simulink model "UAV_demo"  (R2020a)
settings: Solver=FixedStepAuto  StartTime=0.0  StopTime=30  FixedStep=1e-2  RelTol=1e-3
libraries: simulink x7, shared6dof x1

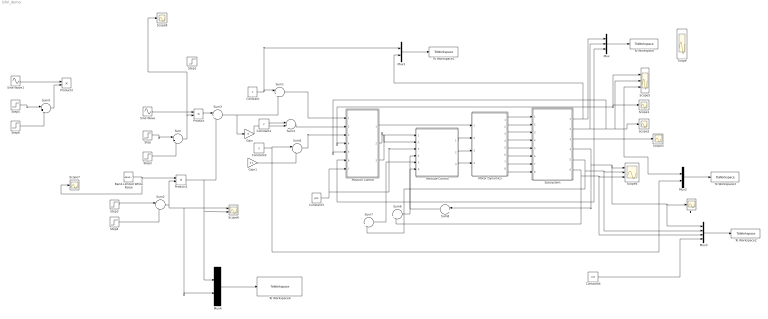
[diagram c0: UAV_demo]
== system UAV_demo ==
  Attitude Control : Subsystem
  Band-Limited White Noise : simulink/Sources/Band-Limited White Noise  Cov=[0.1]  Ts=0.1  seed=[23341]
  Constant : Constant
  Constant1 : Constant  Value=2
  Constant2 : Constant  Value=5
  Constant3 : Constant  Value=pi/4
  Constant4 : Constant  Value=0.8
  Gain : Gain
  Gain1 : Gain  Gain=0.1
  Motor Dynamics : Subsystem
  Mux : Mux  Inputs=3
  Mux1 : Mux  Inputs=2
  Mux2 : Mux  Inputs=2
  Mux3 : Mux
  Mux4 : Mux  Inputs=2
  Position Control : Subsystem
  Product : Product
  Product1 : Product
  Product2 : Product
  Scope : Scope  NumInputPorts=3
  Scope{1..3,7..8} (5 alike) : Scope
  Scope4 : Scope  NumInputPorts=3
  Scope5 : Scope  NumInputPorts=3
  Scope6 : Scope  NumInputPorts=2
  Sine Wave : Sin  Amplitude=0.5  Phase=pi/2  SampleTime=0
  Sine Wave1 : Sin  Amplitude=-0.01  SampleTime=0
  Step : Step  Time=8  After=2  SampleTime=0
  Step1 : Step  Time=0  After=10  SampleTime=0
  Step2 : Step  Time=9  After=-2  SampleTime=0
  Step3 : Step  Time=8  SampleTime=0
  Step4 : Step  Time=8.5  After=-1  SampleTime=0
  Step5 : Step  Time=8  After=2  SampleTime=0
  Step6 : Step  Time=8.5  After=-2  SampleTime=0
  Subsystem : Subsystem
  Sum{,1..9} (10 alike) : Sum  Inputs=|++
  To Workspace : ToWorkspace  VariableName=xyz  SampleTime=-1
  To Workspace1 : ToWorkspace  VariableName=x  SampleTime=-1
  To Workspace2 : ToWorkspace  VariableName=theta  SampleTime=-1
  To Workspace3 : ToWorkspace  VariableName=z  SampleTime=-1
  To Workspace4 : ToWorkspace  VariableName=gu  SampleTime=-1
  横滚角 : Scope
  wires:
  Position Control/2(Roll des) -> Attitude Control/1(Roll des)
  Position Control/3(Pitch des) -> Attitude Control/2(Pitch des)
  Attitude Control/1(Delta Omga roll) -> Motor Dynamics/2(Delta Omga roll)
  Position Control/1(OmegaF) -> Motor Dynamics/1(Delta OmgaF)
  Motor Dynamics/1(F1) -> Subsystem/1(Forces1)
  Motor Dynamics/2(F2) -> Subsystem/2(Forces2)
  Motor Dynamics/3(F3) -> Subsystem/3(Forces3)
  Motor Dynamics/4(F4) -> Subsystem/4(Forces4)
  Motor Dynamics/6(M2) -> Subsystem/6(M2)
  Motor Dynamics/7(M3) -> Subsystem/7(M3)
  Motor Dynamics/8(M4) -> Subsystem/8(M4)
  Subsystem/5(Pitch) -> Mux3/2, Scope4/2, Sum7/2
  Subsystem/4(Roll) -> Mux3/1, 横滚角/1, Scope4/1, Sum8/1
  Attitude Control/2(Delta Omga pitch) -> Motor Dynamics/3(Delta Omga pitch)
  Attitude Control/3(Delta Omga yaw) -> Motor Dynamics/4(Delta Omga yaw)
  Sum4/1 -> Position Control/2(y0)
  Sum5/1 -> Position Control/3(z0)
  Subsystem/2(Y) -> Scope5/2, Scope2/1, Position Control/5(y1), Mux/2
  Subsystem/3(Z) -> Mux2/1, Scope3/1, Scope5/3, Mux/3, Position Control/6(z1)
  Subsystem/1(X) -> Mux1/2, Scope1/1, Scope5/1, Mux/1, Position Control/4(x1)
  Constant3/1 -> Position Control/7(yaw), Attitude Control/3(Yaw des)
  Motor Dynamics/5(M1) -> Subsystem/5(M1)
  Step/1 -> Sum/1
  Sum/1 -> Scope8/1, Product/2
  Constant/1 -> Mux1/1, Sum1/1
  Sum1/1 -> Position Control/1(x0)
  Product1/1 -> Scope6/2, Mux4/1, Sum3/2
  Sum2/1 -> Product1/2, Mux4/2, Scope6/1
  Band-Limited White Noise/1 -> Scope7/1, Product1/1
  Step4/1 -> Sum2/2
  Step3/1 -> Sum2/1
  Product/1 -> Sum3/1
  Constant1/1 -> Sum4/1
  Constant2/1 -> Sum5/1, Mux2/2
  Sum6/1 -> Attitude Control/6(Yaw)
  Sum7/1 -> Attitude Control/5(Pitch)
  Sum8/1 -> Attitude Control/4(roll)
  Mux/1 -> To Workspace/1
  Mux1/1 -> To Workspace1/1
  Mux2/1 -> To Workspace3/1
  Mux3/1 -> To Workspace2/1
  Subsystem/6(Yaw) -> Sum6/2, Mux3/3, Scope4/3
  Constant4/1 -> Mux3/4
  Sine Wave/1 -> Product/1
  Sine Wave1/1 -> Product2/1
  Sum9/1 -> Product2/2
  Step6/1 -> Sum9/2
  Step5/1 -> Sum9/1
  Mux4/1 -> To Workspace4/1
  Gain/1 -> Sum4/2
  Gain1/1 -> Sum5/2
  Step2/1 -> Sum/2
  Sum3/1 -> Gain/1, Sum1/2

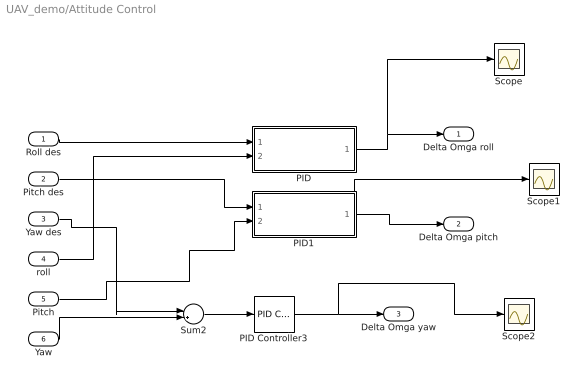
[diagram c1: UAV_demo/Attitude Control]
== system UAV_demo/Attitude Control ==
  Roll des : Inport
  Pitch des : Inport  Port=2
  Yaw des : Inport  Port=3
  roll : Inport  Port=4
  Pitch : Inport  Port=5
  Yaw : Inport  Port=6
  PID : Subsystem
  PID Controller3 : simulink/Continuous/PID Controller  Controller=PD  Form=Parallel  TimeDomain=Continuous-time  UseExternalTs=off  SampleTime=-1  IntegratorMethod=Forward Euler  FilterMethod=Forward Euler  ControllerParametersSource=internal  P=120  I=1  D=120  UseFilter=on  N=100  TunerSelectOption=Transfer Function Based (PID Tuner App)  InitialConditionSource=internal  InitialConditionForIntegrator=0  InitialConditionForFilter=0  DifferentiatorICPrevScaledInput=0  ExternalReset=none  TrackingMode=off  Kt=1  LimitOutput=off  UpperSaturationLimit=inf  LowerSaturationLimit=-inf  LinearizeAsGain=on  AntiWindupMode=none  Kb=1  POutMin=[]  POutMax=[]  IOutMin=[]  IOutMax=[]  DOutMin=[]  DOutMax=[]  NOutMin=[]  NOutMax=[]  SumOutMin=[]  SumOutMax=[]  SaturationOutMin=[]  SaturationOutMax=[]  PParamMin=[]  PParamMax=[]  IParamMin=[]  IParamMax=[]  DParamMin=[]  DParamMax=[]  NParamMin=[]  NParamMax=[]  KbParamMin=[]  KbParamMax=[]  KtParamMin=[]  KtParamMax=[]  KbOutMin=[]  KbOutMax=[]  KtOutMin=[]  KtOutMax=[]  IntegratorOutMin=[]  IntegratorOutMax=[]  FilterOutMin=[]  FilterOutMax=[]  SumI1OutMin=[]  SumI1OutMax=[]  SumI2OutMin=[]  SumI2OutMax=[]  SumI3OutMin=[]  SumI3OutMax=[]  SumI4OutMin=[]  SumI4OutMax=[]  SumDOutMin=[]  SumDOutMax=[]  DifferentiatorOutMin=[]  DifferentiatorOutMax=[]  FilterDiffOutCoefMin=[]  FilterDiffOutCoefMax=[]  ReciprocalOutMin=[]  ReciprocalOutMax=[]  SumDenOutMin=[]  SumDenOutMax=[]  SumNumOutMin=[]  SumNumOutMax=[]  DivideOutMin=[]  DivideOutMax=[]  UdiffTsProdOutMin=[]  UdiffTsProdOutMax=[]  NTsProdOutMin=[]  NTsProdOutMax=[]  UintegralTsProdOutMin=[]  UintegralTsProdOutMax=[]  UngainTsProdOutMin=[]  UngainTsProdOutMax=[]  IntegratorContinuousStateAttributes=''  IntegratorStateMustResolveToSignalObject=off  IntegratorRTWStateStorageClass=Auto  FilterContinuousStateAttributes=''  FilterStateMustResolveToSignalObject=off  FilterRTWStateStorageClass=Auto  ParallelPVariant=InternalParameters  IdealPVariant=Disabled  IVariant=Disabled  DVariant=InternalParameters  IntegratorVariant=Disabled  SatVariant=Disabled  AWVariant=Disabled  PCopyVariant=Disabled  TRVariant=Disabled  FdbkBlocksVariant=Forward  IdealPFdbkVariant=Disabled  SatFdbkVariant=Disabled  DerivativeFilterVariant=ContFilter  NVariant=InternalParameters  NCopyVariant=Disabled  FilterICVariant=InternalICsFilter  IntegratorICVariant=Disabled  ExternalResetVariant=Disabled  TRSumVariant=Passthrough  SumFdbkVariant=Disabled  SumVariant=Sum_PD  TsampFilterVariant=InternalTs  TsampNgainVariant=Passthrough  TsampIntegralVariant=Disabled_SignalSpec
  PID1 : Subsystem
  Scope : Scope
  Scope1 : Scope
  Scope2 : Scope
  Sum2 : Sum  Inputs=|+-
  Delta Omga roll : Outport
  Delta Omga pitch : Outport  Port=2
  Delta Omga yaw : Outport  Port=3
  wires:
  roll/1 -> PID/2(x1)
  Pitch/1 -> PID1/2(x1)
  Yaw des/1 -> Sum2/1
  Yaw/1 -> Sum2/2
  Roll des/1 -> PID/1(x0)
  Pitch des/1 -> PID1/1(x0)
  Sum2/1 -> PID Controller3/1
  PID/1(r1..des) -> Scope/1, Delta Omga roll/1
  PID Controller3/1 -> Scope2/1, Delta Omga yaw/1
  PID1/1(r1..des) -> Scope1/1, Delta Omga pitch/1

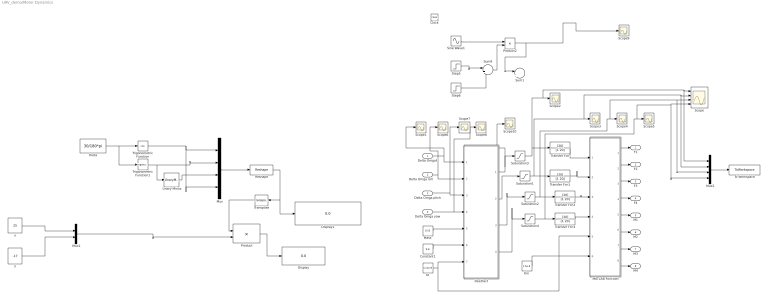
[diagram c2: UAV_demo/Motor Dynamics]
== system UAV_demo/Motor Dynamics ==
  Delta OmgaF : Inport
  Delta Omga roll : Inport  Port=2
  Delta Omga pitch : Inport  Port=3
  Delta Omga yaw : Inport  Port=4
  Clock : Clock
  Constant1 : Constant  Value=9.8
  Des2fact : MATLAB Function  TreatAsAtomicUnit=on
  Display : Display
  Display1 : Display
  Kf : Constant  Value=6.11e-8
  Km : Constant  Value=1.5e-9
  MATLAB Function : MATLAB Function  TreatAsAtomicUnit=on
  Mass : Constant  Value=0.53
  Mux : Mux
  Mux1 : Mux  Inputs=2
  Mux2 : Mux
  Product : Product  Multiplication=Matrix(*)
  Product2 : Product
  Reshape : Reshape  OutputDimensionality=Customize  OutputDimensions=[2,2]
  Saturation{1..4} (4 alike) : Saturate  UpperLimit=7800  LowerLimit=1200
  Scope : Scope  NumInputPorts=4
  Scope{1..10} (10 alike) : Scope
  Sine Wave1 : Sin  Amplitude=-3000  SampleTime=0
  Step5 : Step  Time=8  After=2  SampleTime=0
  Step6 : Step  Time=8.5  After=-2  SampleTime=0
  Sum1 : Sum  Inputs=|++
  Sum9 : Sum  Inputs=|++
  To Workspace : ToWorkspace  VariableName=T  SampleTime=-1
  Transfer Fcn{,1..3} (4 alike) : TransferFcn  Numerator=[20]  Denominator=[1 20]
  Transpose : Math  Operator=transpose
  Trigonometric Function : Trigonometry  Operator=cos
  Trigonometric Function1 : Trigonometry
  Unary Minus : UnaryMinus
  theta : Constant  Value=30/180*pi
  x : Constant  Value=25
  y : Constant  Value=-17
  F1 : Outport
  F2 : Outport  Port=2
  F3 : Outport  Port=3
  F4 : Outport  Port=4
  M1 : Outport  Port=5
  M2 : Outport  Port=6
  M3 : Outport  Port=7
  M4 : Outport  Port=8
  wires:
  MATLAB Function/1(F1) -> F1/1
  MATLAB Function/2(F2) -> F2/1
  MATLAB Function/3(F3) -> F3/1
  MATLAB Function/4(F4) -> F4/1
  MATLAB Function/5(M1) -> M1/1
  MATLAB Function/6(M2) -> M2/1
  MATLAB Function/7(M3) -> M3/1
  MATLAB Function/8(M4) -> M4/1
  Delta OmgaF/1 -> Scope1/1, Des2fact/1(u1)
  Delta Omga roll/1 -> Des2fact/2(u2), Scope6/1
  Delta Omga pitch/1 -> Scope7/1, Des2fact/3(u3)
  Delta Omga yaw/1 -> Scope8/1, Des2fact/4(u4)
  Mass/1 -> Des2fact/5(m)
  Constant1/1 -> Des2fact/6(g)
  Kf/1 -> MATLAB Function/5(Kf), Des2fact/7(Kf)
  Km/1 -> MATLAB Function/6(Km)
  Des2fact/1(Omga1) -> Scope10/1, Saturation3/1
  Des2fact/3(Omga3) -> Saturation2/1
  Des2fact/4(Omga4) -> Saturation4/1
  Saturation1/1 -> Scope/2, Mux2/2, Scope3/1, Transfer Fcn1/1
  Saturation2/1 -> Scope/3, Mux2/3, Scope4/1, Transfer Fcn2/1
  Saturation4/1 -> Scope/4, Mux2/4, Scope5/1, Transfer Fcn3/1
  Transfer Fcn/1 -> MATLAB Function/1(u1)
  Transfer Fcn1/1 -> MATLAB Function/2(u2)
  Transfer Fcn2/1 -> MATLAB Function/3(u3)
  Transfer Fcn3/1 -> MATLAB Function/4(u4)
  theta/1 -> Trigonometric Function1/1, Trigonometric Function/1
  Trigonometric Function/1 -> Mux/4, Mux/1
  Trigonometric Function1/1 -> Unary Minus/1, Mux/2
  Unary Minus/1 -> Mux/3
  Mux/1 -> Reshape/1
  x/1 -> Mux1/1
  y/1 -> Mux1/2
  Reshape/1 -> Display1/1, Transpose/1
  Mux1/1 -> Product/2
  Product/1 -> Display/1
  Transpose/1 -> Product/1
  Mux2/1 -> To Workspace/1
  Saturation3/1 -> Mux2/1, Scope/1, Scope2/1, Transfer Fcn/1
  Sum9/1 -> Product2/2
  Step5/1 -> Sum9/1
  Product2/1 -> Sum1/1, Scope9/1
  Step6/1 -> Sum9/2
  Sine Wave1/1 -> Product2/1
  Des2fact/2(Omga2) -> Saturation1/1

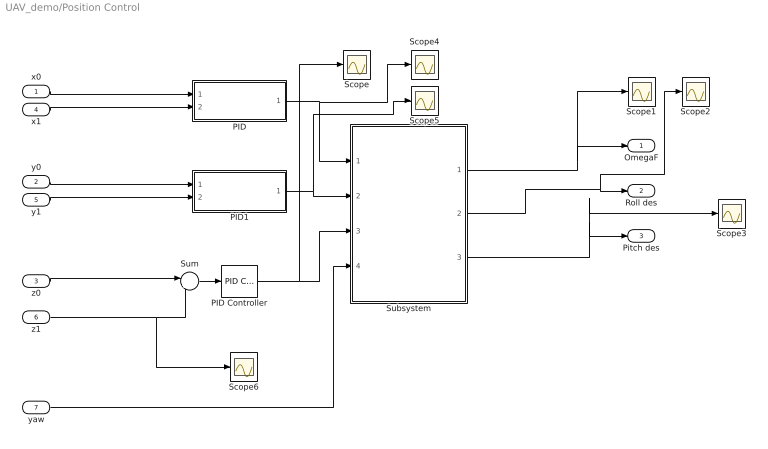
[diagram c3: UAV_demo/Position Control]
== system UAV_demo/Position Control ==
  x0 : Inport
  y0 : Inport  Port=2
  z0 : Inport  Port=3
  x1 : Inport  Port=4
  y1 : Inport  Port=5
  z1 : Inport  Port=6
  yaw : Inport  Port=7
  PID : Subsystem
  PID Controller : simulink/Continuous/PID Controller  Controller=PD  Form=Parallel  TimeDomain=Continuous-time  UseExternalTs=off  SampleTime=-1  IntegratorMethod=Forward Euler  FilterMethod=Forward Euler  ControllerParametersSource=internal  P=60  I=1  D=30  UseFilter=on  N=50  TunerSelectOption=Transfer Function Based (PID Tuner App)  InitialConditionSource=internal  InitialConditionForIntegrator=0  InitialConditionForFilter=0  DifferentiatorICPrevScaledInput=0  ExternalReset=none  TrackingMode=off  Kt=1  LimitOutput=off  UpperSaturationLimit=inf  LowerSaturationLimit=-inf  LinearizeAsGain=on  AntiWindupMode=none  Kb=1  POutMin=[]  POutMax=[]  IOutMin=[]  IOutMax=[]  DOutMin=[]  DOutMax=[]  NOutMin=[]  NOutMax=[]  SumOutMin=[]  SumOutMax=[]  SaturationOutMin=[]  SaturationOutMax=[]  PParamMin=[]  PParamMax=[]  IParamMin=[]  IParamMax=[]  DParamMin=[]  DParamMax=[]  NParamMin=[]  NParamMax=[]  KbParamMin=[]  KbParamMax=[]  KtParamMin=[]  KtParamMax=[]  KbOutMin=[]  KbOutMax=[]  KtOutMin=[]  KtOutMax=[]  IntegratorOutMin=[]  IntegratorOutMax=[]  FilterOutMin=[]  FilterOutMax=[]  SumI1OutMin=[]  SumI1OutMax=[]  SumI2OutMin=[]  SumI2OutMax=[]  SumI3OutMin=[]  SumI3OutMax=[]  SumI4OutMin=[]  SumI4OutMax=[]  SumDOutMin=[]  SumDOutMax=[]  DifferentiatorOutMin=[]  DifferentiatorOutMax=[]  FilterDiffOutCoefMin=[]  FilterDiffOutCoefMax=[]  ReciprocalOutMin=[]  ReciprocalOutMax=[]  SumDenOutMin=[]  SumDenOutMax=[]  SumNumOutMin=[]  SumNumOutMax=[]  DivideOutMin=[]  DivideOutMax=[]  UdiffTsProdOutMin=[]  UdiffTsProdOutMax=[]  NTsProdOutMin=[]  NTsProdOutMax=[]  UintegralTsProdOutMin=[]  UintegralTsProdOutMax=[]  UngainTsProdOutMin=[]  UngainTsProdOutMax=[]  IntegratorContinuousStateAttributes=''  IntegratorStateMustResolveToSignalObject=off  IntegratorRTWStateStorageClass=Auto  FilterContinuousStateAttributes=''  FilterStateMustResolveToSignalObject=off  FilterRTWStateStorageClass=Auto  ParallelPVariant=InternalParameters  IdealPVariant=Disabled  IVariant=Disabled  DVariant=InternalParameters  IntegratorVariant=Disabled  SatVariant=Disabled  AWVariant=Disabled  PCopyVariant=Disabled  TRVariant=Disabled  FdbkBlocksVariant=Forward  IdealPFdbkVariant=Disabled  SatFdbkVariant=Disabled  DerivativeFilterVariant=ContFilter  NVariant=InternalParameters  NCopyVariant=Disabled  FilterICVariant=InternalICsFilter  IntegratorICVariant=Disabled  ExternalResetVariant=Disabled  TRSumVariant=Passthrough  SumFdbkVariant=Disabled  SumVariant=Sum_PD  TsampFilterVariant=InternalTs  TsampNgainVariant=Passthrough  TsampIntegralVariant=Disabled_SignalSpec
  PID1 : Subsystem
  Scope{,1..6} (7 alike) : Scope
  Subsystem : Subsystem
  Sum : Sum  Inputs=|+-
  OmegaF : Outport
  Roll des : Outport  Port=2
  Pitch des : Outport  Port=3
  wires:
  x0/1 -> PID/1(x0)
  x1/1 -> PID/2(x1)
  z1/1 -> Scope6/1, Sum/2
  z0/1 -> Sum/1
  PID1/1(r2..des) -> Scope5/1, Subsystem/2(r2..des)
  PID Controller/1 -> Scope/1, Subsystem/3(r3..des)
  Subsystem/1(OmgaF) -> Scope1/1, OmegaF/1
  PID/1(r1..des) -> Subsystem/1(r1..des), Scope4/1
  y0/1 -> PID1/1(y0)
  y1/1 -> PID1/2(y1)
  yaw/1 -> Subsystem/4(yaw)
  Sum/1 -> PID Controller/1
  Subsystem/2(roll) -> Scope2/1, Roll des/1
  Subsystem/3(pitch) -> Scope3/1, Pitch des/1

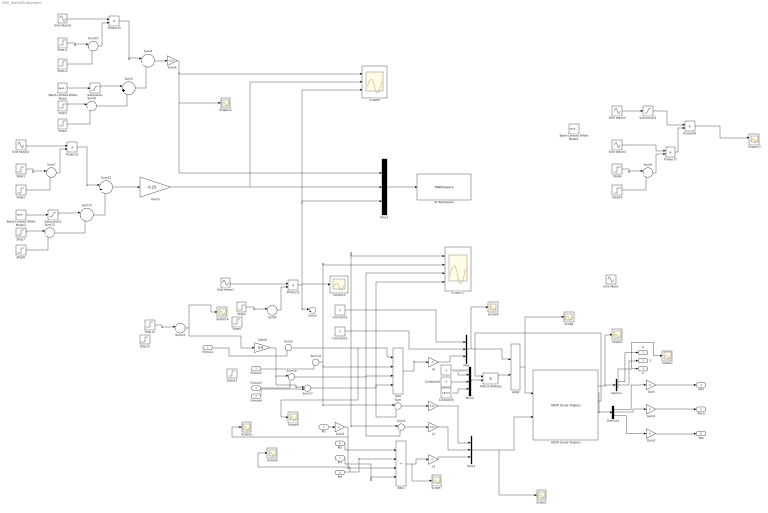
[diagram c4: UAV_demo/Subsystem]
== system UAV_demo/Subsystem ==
  Forces1 : Inport
  Forces2 : Inport  Port=2
  Forces3 : Inport  Port=3
  Forces4 : Inport  Port=4
  M1 : Inport  Port=5
  M2 : Inport  Port=6
  M3 : Inport  Port=7
  M4 : Inport  Port=8
  6DOF (Euler Angles) : shared6dof/6DOF (Euler Angles)  units=Metric (MKS)  mtype=Fixed  rep=Quaternion  xme_0=[0 0 0]  Vm_0=[0 0 0]  eul_0=[0 0 0]  pm_0=[0 0 0]  mass_0=0.53  mass_e=0.5  mass_f=2.0  inertia=[1.745e-3 0 0;0 1.745e-3 0;0 0 3.475e-3]  inertia_e=eye(3)  inertia_f=2*eye(3)  k_quat=1.0  vre_flag=on  abi_flag=off  aMode=0  xme_statename=''  Vm_statename=''  eul_statename=''  quat_statename=''  pm_statename=''  mass_statename=''
  Add : Sum  Inputs=++++
  Add1 : Sum  Inputs=++--
  Add2 : Sum
  Band-Limited White Noise : simulink/Sources/Band-Limited White Noise  Cov=[0.01]  Ts=0.1  seed=[23341]
  Band-Limited White Noise1 : simulink/Sources/Band-Limited White Noise  Cov=[0.01]  Ts=0.1  seed=[23341]
  Band-Limited White Noise2 : simulink/Sources/Band-Limited White Noise  Cov=[0.01]  Ts=0.1  seed=[23341]
  Constant{1..4} (4 alike) : Constant  Value=0
  Constant5 : Constant  Value=9.8*0.53
  Demux : Demux  Outputs=3
  Demux1 : Demux  Outputs=3
  Gain{,1..3} (4 alike) : Gain
  Gain4 : Gain  Gain=-0.23
  Gain5 : Gain  Gain=-0.25
  Gain6 : Gain  Gain=0.9
  L : Gain  Gain=0.01
  L1 : Gain  Gain=0.01
  L2 : Gain  Gain=-1
  L3 : Gain
  Matrix Multiply : Product  Multiplication=Matrix(*)
  Mux{,1..3} (4 alike) : Mux  Inputs=3
  Product{1..3,6..7} (5 alike) : Product
  Saturation : Saturate  UpperLimit=0.007  LowerLimit=-0.007
  Saturation1 : Saturate  UpperLimit=0.02  LowerLimit=-0.007
  Saturation2 : Saturate  UpperLimit=0.01  LowerLimit=-0.16
  Scope{,1..7,9..10,12,14} (12 alike) : Scope
  Scope11 : Scope  NumInputPorts=4
  Scope13 : Scope  NumInputPorts=2
  Scope8 : Scope  NumInputPorts=3
  Sine Wave : Sin  SampleTime=0
  Sine Wave1 : Sin  Amplitude=-0.08  Phase=pi/2  SampleTime=0
  Sine Wave2 : Sin  Amplitude=-0.1  SampleTime=0
  Sine Wave3 : Sin  Amplitude=-0.1  SampleTime=0
  Sine Wave4 : Sin  Amplitude=-0.12  SampleTime=0
  Sine Wave5 : Sin  Amplitude=-0.1  SampleTime=0
  Step{1,5,9,11} (4 alike) : Step  Time=8  After=2  SampleTime=0
  Step10 : Step  Time=8.5  After=-2  SampleTime=0
  Step12 : Step  Time=8.5  After=-2  SampleTime=0
  Step13 : Step  Time=8.5  After=-0.4  SampleTime=0
  Step14 : Step  Time=8  SampleTime=0
  Step15 : Step  Time=8.5  After=-1  SampleTime=0
  Step2 : Step  Time=8.5  After=-2  SampleTime=0
  Step3 : Step  Time=8  SampleTime=0
  Step4 : Step  Time=8.5  After=-1  SampleTime=0
  Step6 : Step  Time=8.5  After=-0.5  SampleTime=0
  Step7 : Step  Time=8  SampleTime=0
  Step8 : Step  Time=8.5  After=-1  SampleTime=0
  Sum : Sum  Inputs=|+-
  Sum1 : Sum  Inputs=|+-
  Sum{2..17} (16 alike) : Sum  Inputs=|++
  To Workspace : ToWorkspace  VariableName=observe  SampleTime=-1
  X : Outport
  Y : Outport  Port=2
  Z : Outport  Port=3
  Roll : Outport  Port=4
  Pitch : Outport  Port=5
  Yaw : Outport  Port=6
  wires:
  Mux/1 -> Scope4/1, Add2/1
  Add/1 -> L2/1
  Sum/1 -> L/1
  Sum1/1 -> L1/1
  M2/1 -> Add1/1
  M4/1 -> Scope6/1, Add1/2
  M1/1 -> Gain3/1
  M3/1 -> Add1/4
  L/1 -> Mux1/1
  L1/1 -> Mux1/2
  Add1/1 -> Scope7/1, L3/1
  6DOF (Euler Angles)/3 -> Demux1/1
  Demux/1 -> X/1
  Demux/2 -> Y/1
  Demux/3 -> Scope2/1, Z/1
  L2/1 -> Mux/3
  Constant2/1 -> Mux/2
  Constant1/1 -> Mux/1
  Add2/1 -> 6DOF (Euler Angles)/1, Scope/1
  Matrix Multiply/1 -> Add2/2
  Constant3/1 -> Mux2/1
  Constant4/1 -> Mux2/2
  Constant5/1 -> Mux2/3
  Mux2/1 -> Matrix Multiply/2
  6DOF (Euler Angles)/4 -> Matrix Multiply/1
  Mux1/1 -> Scope1/1, 6DOF (Euler Angles)/2
  Demux1/3 -> Gain2/1
  Demux1/2 -> Gain1/1
  Demux1/1 -> Gain/1
  L3/1 -> Mux1/3
  Gain/1 -> Roll/1
  Gain1/1 -> Pitch/1
  Gain2/1 -> Yaw/1
  6DOF (Euler Angles)/2 -> Scope3/1, Demux/1
  Gain3/1 -> Scope5/1, Add1/3
  Step5/1 -> Sum9/1
  Sum9/1 -> Product2/2
  Product2/1 -> Mux3/3, Scope8/3, Scope10/1, Sum2/1
  Band-Limited White Noise/1 -> Saturation/1
  Mux3/1 -> To Workspace/1
  Sum6/1 -> Sum5/2
  Step4/1 -> Sum6/2
  Step3/1 -> Sum6/1
  Saturation/1 -> Sum5/1
  Saturation2/1 -> Product6/1
  Step9/1 -> Sum8/1
  Step10/1 -> Sum8/2
  Product6/1 -> Scope13/1
  Sine Wave3/1 -> Product7/1
  Sum8/1 -> Product7/2
  Product7/1 -> Product6/2
  Sine Wave4/1 -> Saturation2/1
  Sum5/1 -> Sum4/2
  Sine Wave5/1 -> Product3/1
  Sum10/1 -> Product3/2
  Step11/1 -> Sum10/1
  Step12/1 -> Sum10/2
  Product3/1 -> Sum4/1
  Sum4/1 -> Gain4/1
  Gain4/1 -> Scope12/1, Mux3/1, Scope8/1
  Sum11/1 -> Gain5/1
  Product1/1 -> Sum11/1
  Step2/1 -> Sum7/2
  Step1/1 -> Sum7/1
  Sum7/1 -> Product1/2
  Sine Wave2/1 -> Product1/1
  Sum12/1 -> Sum11/2
  Saturation1/1 -> Sum12/1
  Step7/1 -> Sum13/1
  Step8/1 -> Sum13/2
  Sum13/1 -> Sum12/2
  Band-Limited White Noise2/1 -> Saturation1/1
  Gain5/1 -> Scope8/2, Mux3/2
  Sine Wave1/1 -> Product2/1
  Sum3/1 -> Sum1/1, Scope9/1, Add/1, Scope11/1
  Sum14/1 -> Sum/1, Add/2, Scope11/2
  Forces2/1 -> Sum14/2
  Sum15/1 -> Scope14/1, Gain6/1
  Step14/1 -> Sum15/1
  Forces1/1 -> Sum3/2
  Sum16/1 -> Scope11/3, Add/3, Sum1/2
  Forces3/1 -> Sum16/2
  Gain6/1 -> Sum17/1, Sum16/1
  Sum17/1 -> Sum/2, Scope11/4, Add/4
  Forces4/1 -> Sum17/2

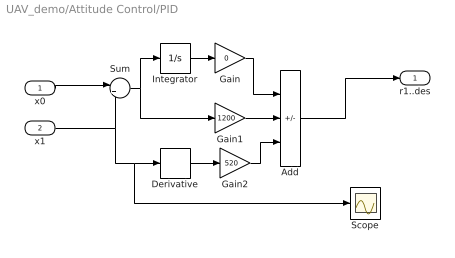
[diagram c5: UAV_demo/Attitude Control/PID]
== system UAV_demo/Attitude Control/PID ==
  x0 : Inport
  x1 : Inport  Port=2
  Add : Sum  Inputs=++-
  Derivative : Derivative
  Gain : Gain  Gain=0
  Gain1 : Gain  Gain=1200
  Gain2 : Gain  Gain=520
  Integrator : Integrator
  Scope : Scope
  Sum : Sum  Inputs=|+-
  r1..des : Outport
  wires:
  x0/1 -> Sum/1
  x1/1 -> Scope/1, Derivative/1, Sum/2
  Sum/1 -> Gain1/1, Integrator/1
  Integrator/1 -> Gain/1
  Gain/1 -> Add/1
  Gain1/1 -> Add/2
  Derivative/1 -> Gain2/1
  Gain2/1 -> Add/3
  Add/1 -> r1..des/1

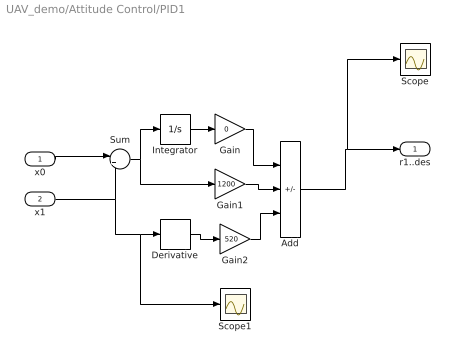
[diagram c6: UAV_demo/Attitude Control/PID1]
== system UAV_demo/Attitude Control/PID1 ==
  x0 : Inport
  x1 : Inport  Port=2
  Add : Sum  Inputs=++-
  Derivative : Derivative
  Gain : Gain  Gain=0
  Gain1 : Gain  Gain=1200
  Gain2 : Gain  Gain=520
  Integrator : Integrator
  Scope : Scope
  Scope1 : Scope
  Sum : Sum  Inputs=|+-
  r1..des : Outport
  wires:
  Add/1 -> Scope/1, r1..des/1
  Gain2/1 -> Add/3
  Derivative/1 -> Gain2/1
  Gain1/1 -> Add/2
  Gain/1 -> Add/1
  Integrator/1 -> Gain/1
  Sum/1 -> Integrator/1, Gain1/1
  x1/1 -> Scope1/1, Derivative/1, Sum/2
  x0/1 -> Sum/1

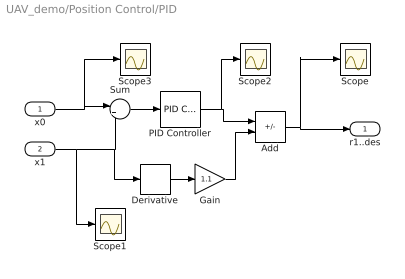
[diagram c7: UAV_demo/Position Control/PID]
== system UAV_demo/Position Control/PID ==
  x0 : Inport
  x1 : Inport  Port=2
  Add : Sum  Inputs=+-
  Derivative : Derivative
  Gain : Gain  Gain=1.1
  PID Controller : simulink/Continuous/PID Controller  Controller=PI  Form=Parallel  TimeDomain=Continuous-time  UseExternalTs=off  SampleTime=-1  IntegratorMethod=Forward Euler  FilterMethod=Forward Euler  ControllerParametersSource=internal  P=0.55  I=0.01  D=0  UseFilter=on  N=100  TunerSelectOption=Transfer Function Based (PID Tuner App)  InitialConditionSource=internal  InitialConditionForIntegrator=0  InitialConditionForFilter=0  DifferentiatorICPrevScaledInput=0  ExternalReset=none  TrackingMode=off  Kt=1  LimitOutput=off  UpperSaturationLimit=inf  LowerSaturationLimit=-inf  LinearizeAsGain=on  AntiWindupMode=none  Kb=1  POutMin=[]  POutMax=[]  IOutMin=[]  IOutMax=[]  DOutMin=[]  DOutMax=[]  NOutMin=[]  NOutMax=[]  SumOutMin=[]  SumOutMax=[]  SaturationOutMin=[]  SaturationOutMax=[]  PParamMin=[]  PParamMax=[]  IParamMin=[]  IParamMax=[]  DParamMin=[]  DParamMax=[]  NParamMin=[]  NParamMax=[]  KbParamMin=[]  KbParamMax=[]  KtParamMin=[]  KtParamMax=[]  KbOutMin=[]  KbOutMax=[]  KtOutMin=[]  KtOutMax=[]  IntegratorOutMin=[]  IntegratorOutMax=[]  FilterOutMin=[]  FilterOutMax=[]  SumI1OutMin=[]  SumI1OutMax=[]  SumI2OutMin=[]  SumI2OutMax=[]  SumI3OutMin=[]  SumI3OutMax=[]  SumI4OutMin=[]  SumI4OutMax=[]  SumDOutMin=[]  SumDOutMax=[]  DifferentiatorOutMin=[]  DifferentiatorOutMax=[]  FilterDiffOutCoefMin=[]  FilterDiffOutCoefMax=[]  ReciprocalOutMin=[]  ReciprocalOutMax=[]  SumDenOutMin=[]  SumDenOutMax=[]  SumNumOutMin=[]  SumNumOutMax=[]  DivideOutMin=[]  DivideOutMax=[]  UdiffTsProdOutMin=[]  UdiffTsProdOutMax=[]  NTsProdOutMin=[]  NTsProdOutMax=[]  UintegralTsProdOutMin=[]  UintegralTsProdOutMax=[]  UngainTsProdOutMin=[]  UngainTsProdOutMax=[]  IntegratorContinuousStateAttributes=''  IntegratorStateMustResolveToSignalObject=off  IntegratorRTWStateStorageClass=Auto  FilterContinuousStateAttributes=''  FilterStateMustResolveToSignalObject=off  FilterRTWStateStorageClass=Auto  ParallelPVariant=InternalParameters  IdealPVariant=Disabled  IVariant=InternalParameters  DVariant=Disabled  IntegratorVariant=Continuous  SatVariant=Disabled  AWVariant=Passthrough  PCopyVariant=Disabled  TRVariant=Disabled  FdbkBlocksVariant=Forward  IdealPFdbkVariant=Disabled  SatFdbkVariant=Disabled  DerivativeFilterVariant=Disabled  NVariant=Disabled  NCopyVariant=Disabled_SignalSpec  FilterICVariant=Disabled  IntegratorICVariant=InternalICs  ExternalResetVariant=Disabled  TRSumVariant=Passthrough  SumFdbkVariant=Disabled  SumVariant=Sum_PI  TsampFilterVariant=InternalTs  TsampNgainVariant=Passthrough  TsampIntegralVariant=Passthrough
  Scope{,1..3} (4 alike) : Scope
  Sum : Sum  Inputs=|+-
  r1..des : Outport
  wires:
  x0/1 -> Scope3/1, Sum/1
  x1/1 -> Scope1/1, Derivative/1, Sum/2
  Sum/1 -> PID Controller/1
  PID Controller/1 -> Scope2/1, Add/1
  Derivative/1 -> Gain/1
  Add/1 -> r1..des/1, Scope/1
  Gain/1 -> Add/2

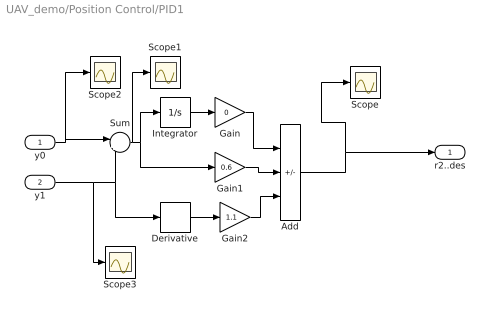
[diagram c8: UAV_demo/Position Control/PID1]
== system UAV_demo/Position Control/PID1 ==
  y0 : Inport
  y1 : Inport  Port=2
  Add : Sum  Inputs=++-
  Derivative : Derivative
  Gain : Gain  Gain=0
  Gain1 : Gain  Gain=0.6
  Gain2 : Gain  Gain=1.1
  Integrator : Integrator
  Scope{,1..3} (4 alike) : Scope
  Sum : Sum  Inputs=|+-
  r2..des : Outport
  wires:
  Gain2/1 -> Add/3
  Derivative/1 -> Gain2/1
  Gain1/1 -> Add/2
  Gain/1 -> Add/1
  Integrator/1 -> Gain/1
  Sum/1 -> Scope1/1, Integrator/1, Gain1/1
  y1/1 -> Scope3/1, Sum/2, Derivative/1
  y0/1 -> Scope2/1, Sum/1
  Add/1 -> r2..des/1, Scope/1

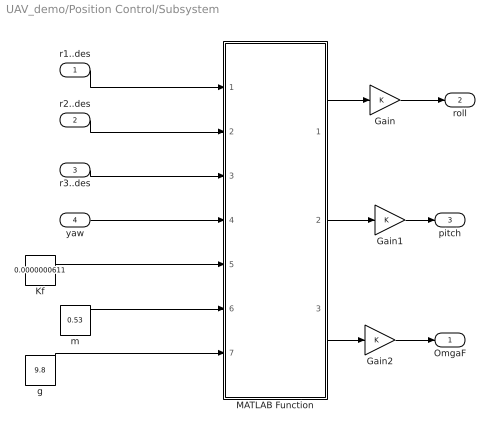
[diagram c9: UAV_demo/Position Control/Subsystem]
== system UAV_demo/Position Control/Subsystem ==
  r1..des : Inport
  r2..des : Inport  Port=2
  r3..des : Inport  Port=3
  yaw : Inport  Port=4
  Gain : Gain
  Gain1 : Gain
  Gain2 : Gain
  Kf : Constant  Value=0.0000000611
  MATLAB Function : MATLAB Function  TreatAsAtomicUnit=on
  g : Constant  Value=9.8
  m : Constant  Value=0.53
  OmgaF : Outport
  roll : Outport  Port=2
  pitch : Outport  Port=3
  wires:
  r1..des/1 -> MATLAB Function/1(r1)
  r2..des/1 -> MATLAB Function/2(r2)
  r3..des/1 -> MATLAB Function/3(r3)
  Kf/1 -> MATLAB Function/5(k)
  m/1 -> MATLAB Function/6(m)
  g/1 -> MATLAB Function/7(g)
  MATLAB Function/1(x) -> Gain/1
  MATLAB Function/2(y) -> Gain1/1
  MATLAB Function/3(z) -> Gain2/1
  yaw/1 -> MATLAB Function/4(fai)
  Gain/1 -> roll/1
  Gain1/1 -> pitch/1
  Gain2/1 -> OmgaF/1

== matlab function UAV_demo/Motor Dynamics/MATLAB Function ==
function [F1,F2,F3,F4,M1,M2,M3,M4] = fcn(u1,u2,u3,u4,Kf,Km)
Omga1 = u1;
Omga2 = u2;
Omga3 = u3;
Omga4 = u4;
F1 = Kf*(Omga1)^2;
F2 = Kf*(Omga2)^2;
F3 = Kf*(Omga3)^2;
F4 = Kf*(Omga4)^2;
M1 = Km*(Omga1)^2;
M2 = Km*(Omga2)^2;
M3 = Km*(Omga3)^2;
M4 = Km*(Omga4)^2;

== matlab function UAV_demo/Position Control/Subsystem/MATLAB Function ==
function [x,y,z] = fcn(r1,r2,r3,fai,k,m,g)
 Omga = sqrt(m*g/4/k);
 x = -1/g*(r1*sin(fai) - r2*cos(fai));
 y = -1/g*(r1*cos(fai) + r2*sin(fai));
 z = -m*r3/8/k/Omga;
%  x = mod(x1,pi/4);
%  y = mod(y1,pi/4);
%  z = mod(z1,pi/4);

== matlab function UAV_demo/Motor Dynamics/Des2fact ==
function [Omga1,Omga2,Omga3,Omga4] = fcn(u1,u2,u3,u4,m,g,Kf)
Omgah = sqrt(m*g/4/Kf);
Omga1 = Omgah+u1+u3-u4;
Omga2 = Omgah+u1+u2+u4;
Omga3 = Omgah+u1-u3-u4;
Omga4 = Omgah+u1-u2+u4;
